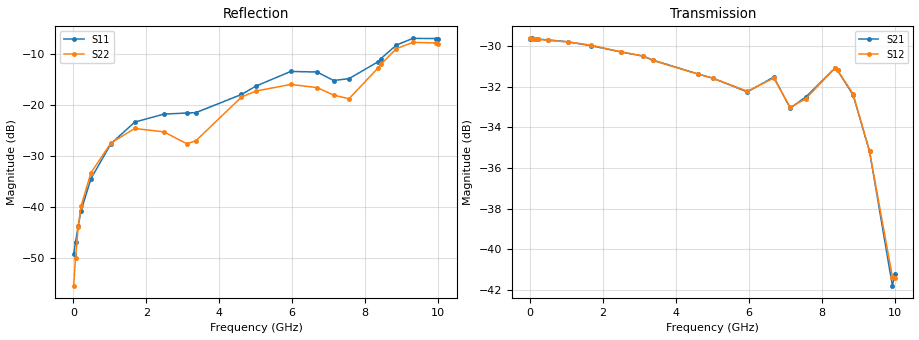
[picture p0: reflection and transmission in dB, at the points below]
! Device ID: PE43704
! Dir: z:\PE43704\PE43704_Char_1_20130516\PE43704\AMB\3p400V\28p75dB
! Serial: 14
! Insertion: A
! Impedance: 50 ohm
! Temp: Amb
! VDD: 3.400V
! Attenuation Step: 28.75dB
! IDD: 1.139658e-01mA
#  Hz  S  RI  R  50
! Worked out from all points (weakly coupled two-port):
!   401 points, 10 MHz to 10.01 GHz, reference 50 ohm
!   highest |S21| = -29.64 dB at 60 MHz (marker M1); lowest = -41.8 dB at 9.935 GHz (marker M2)
!   lowest |S11| = -49.1 dB at 10 MHz (marker M3), VSWR 1.01, Z = 50.4 + j0.0379 ohm
!   |S11| at or under -10 dB: start of sweep to 8.564 GHz
!   |S22| runs from -55.3 to -7.6 dB; largest |S21 - S12| = 0.00066
!   S11 on the Smith chart (normalised r, x): 10 MHz: 1.01, +0.00; 4.61 GHz: 0.79, +0.08; 8.435 GHz: 0.76, +0.46; 9.31 GHz: 0.51, +0.52; 10.01 GHz: 0.44, +0.31
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1e7  0.00349 0.000376  0.0329 -8.13e-05  0.033 -4.94e-05  -0.00166 0.000428
6e7  0.00372 0.00267  0.033 -0.000523  0.0329 -0.000475  -0.00131 0.00288
1.35e8  0.00324 0.00573  0.0329 -0.00114  0.0329 -0.0011  -0.00169 0.00624
2.1e8  0.00205 0.00897  0.0328 -0.00173  0.0328 -0.00172  -0.00273 0.00983
4.85e8  -0.00549 0.0183  0.0325 -0.00385  0.0324 -0.00381  -0.00959 0.0196
1.035e9  -0.0348 0.0236  0.0314 -0.00785  0.0314 -0.0078  -0.0345 0.0251
1.685e9  -0.0678 0.00653  0.0292 -0.0122  0.0293 -0.0122  -0.0584 0.00831
2.485e9  -0.0798 -0.0168  0.0256 -0.0167  0.0257 -0.0166  -0.0542 -0.00705
3.11e9  -0.0818 -0.017  0.0225 -0.0196  0.0225 -0.0196  -0.0417 0.00341
3.36e9  -0.0836 -0.0107  0.0209 -0.0204  0.0209 -0.0203  -0.043 0.0122
4.61e9  -0.1166 0.05  0.0144 -0.0228  0.0145 -0.0227  -0.102 0.0626
5.01e9  -0.1358 0.0712  0.0132 -0.0228  0.0132 -0.0228  -0.1227 0.0612
5.96e9  -0.1864 0.103  0.00861 -0.0228  0.00862 -0.0229  -0.1483 0.0569
6.685e9  -0.187 0.0963  0.00691 -0.0256  0.00662 -0.0255  -0.1378 0.0543
7.135e9  -0.1545 0.0794  0.00234 -0.0221  0.00238 -0.0222  -0.1042 0.0692
7.56e9  -0.1294 0.1268  0.00291 -0.0235  0.00256 -0.0233  -0.0693 0.092
8.36e9  -0.059 0.2589  -0.00561 -0.0273  -0.00567 -0.0273  -0.0773 0.2184
8.435e9  -0.0602 0.2785  -0.00704 -0.0266  -0.00713 -0.0266  -0.0862 0.2355
8.86e9  -0.1003 0.3726  -0.0125 -0.0204  -0.0128 -0.0204  -0.1438 0.3258
9.31e9  -0.1826 0.4096  -0.012 -0.0126  -0.012 -0.0126  -0.2277 0.3405
9.935e9  -0.3173 0.3143  -0.00298 -0.00757  -0.0032 -0.00794  -0.3498 0.2032
1.001e10  -0.3287 0.2887  -0.00201 -0.00846  -0.00171 -0.00831  -0.3589 0.1745
